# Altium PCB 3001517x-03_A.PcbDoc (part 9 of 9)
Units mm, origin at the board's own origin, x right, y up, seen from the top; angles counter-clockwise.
Board outline 100 x 72 mm, 10 copper layers (Top, GND_2, Signal_3, Signal_4, PWR_5, GND_6, Signal_7, Signal_8, GND_9, Bottom), stack 1.6 mm thick; 602 components, 497 nets, 2372 pads, 1602 vias.

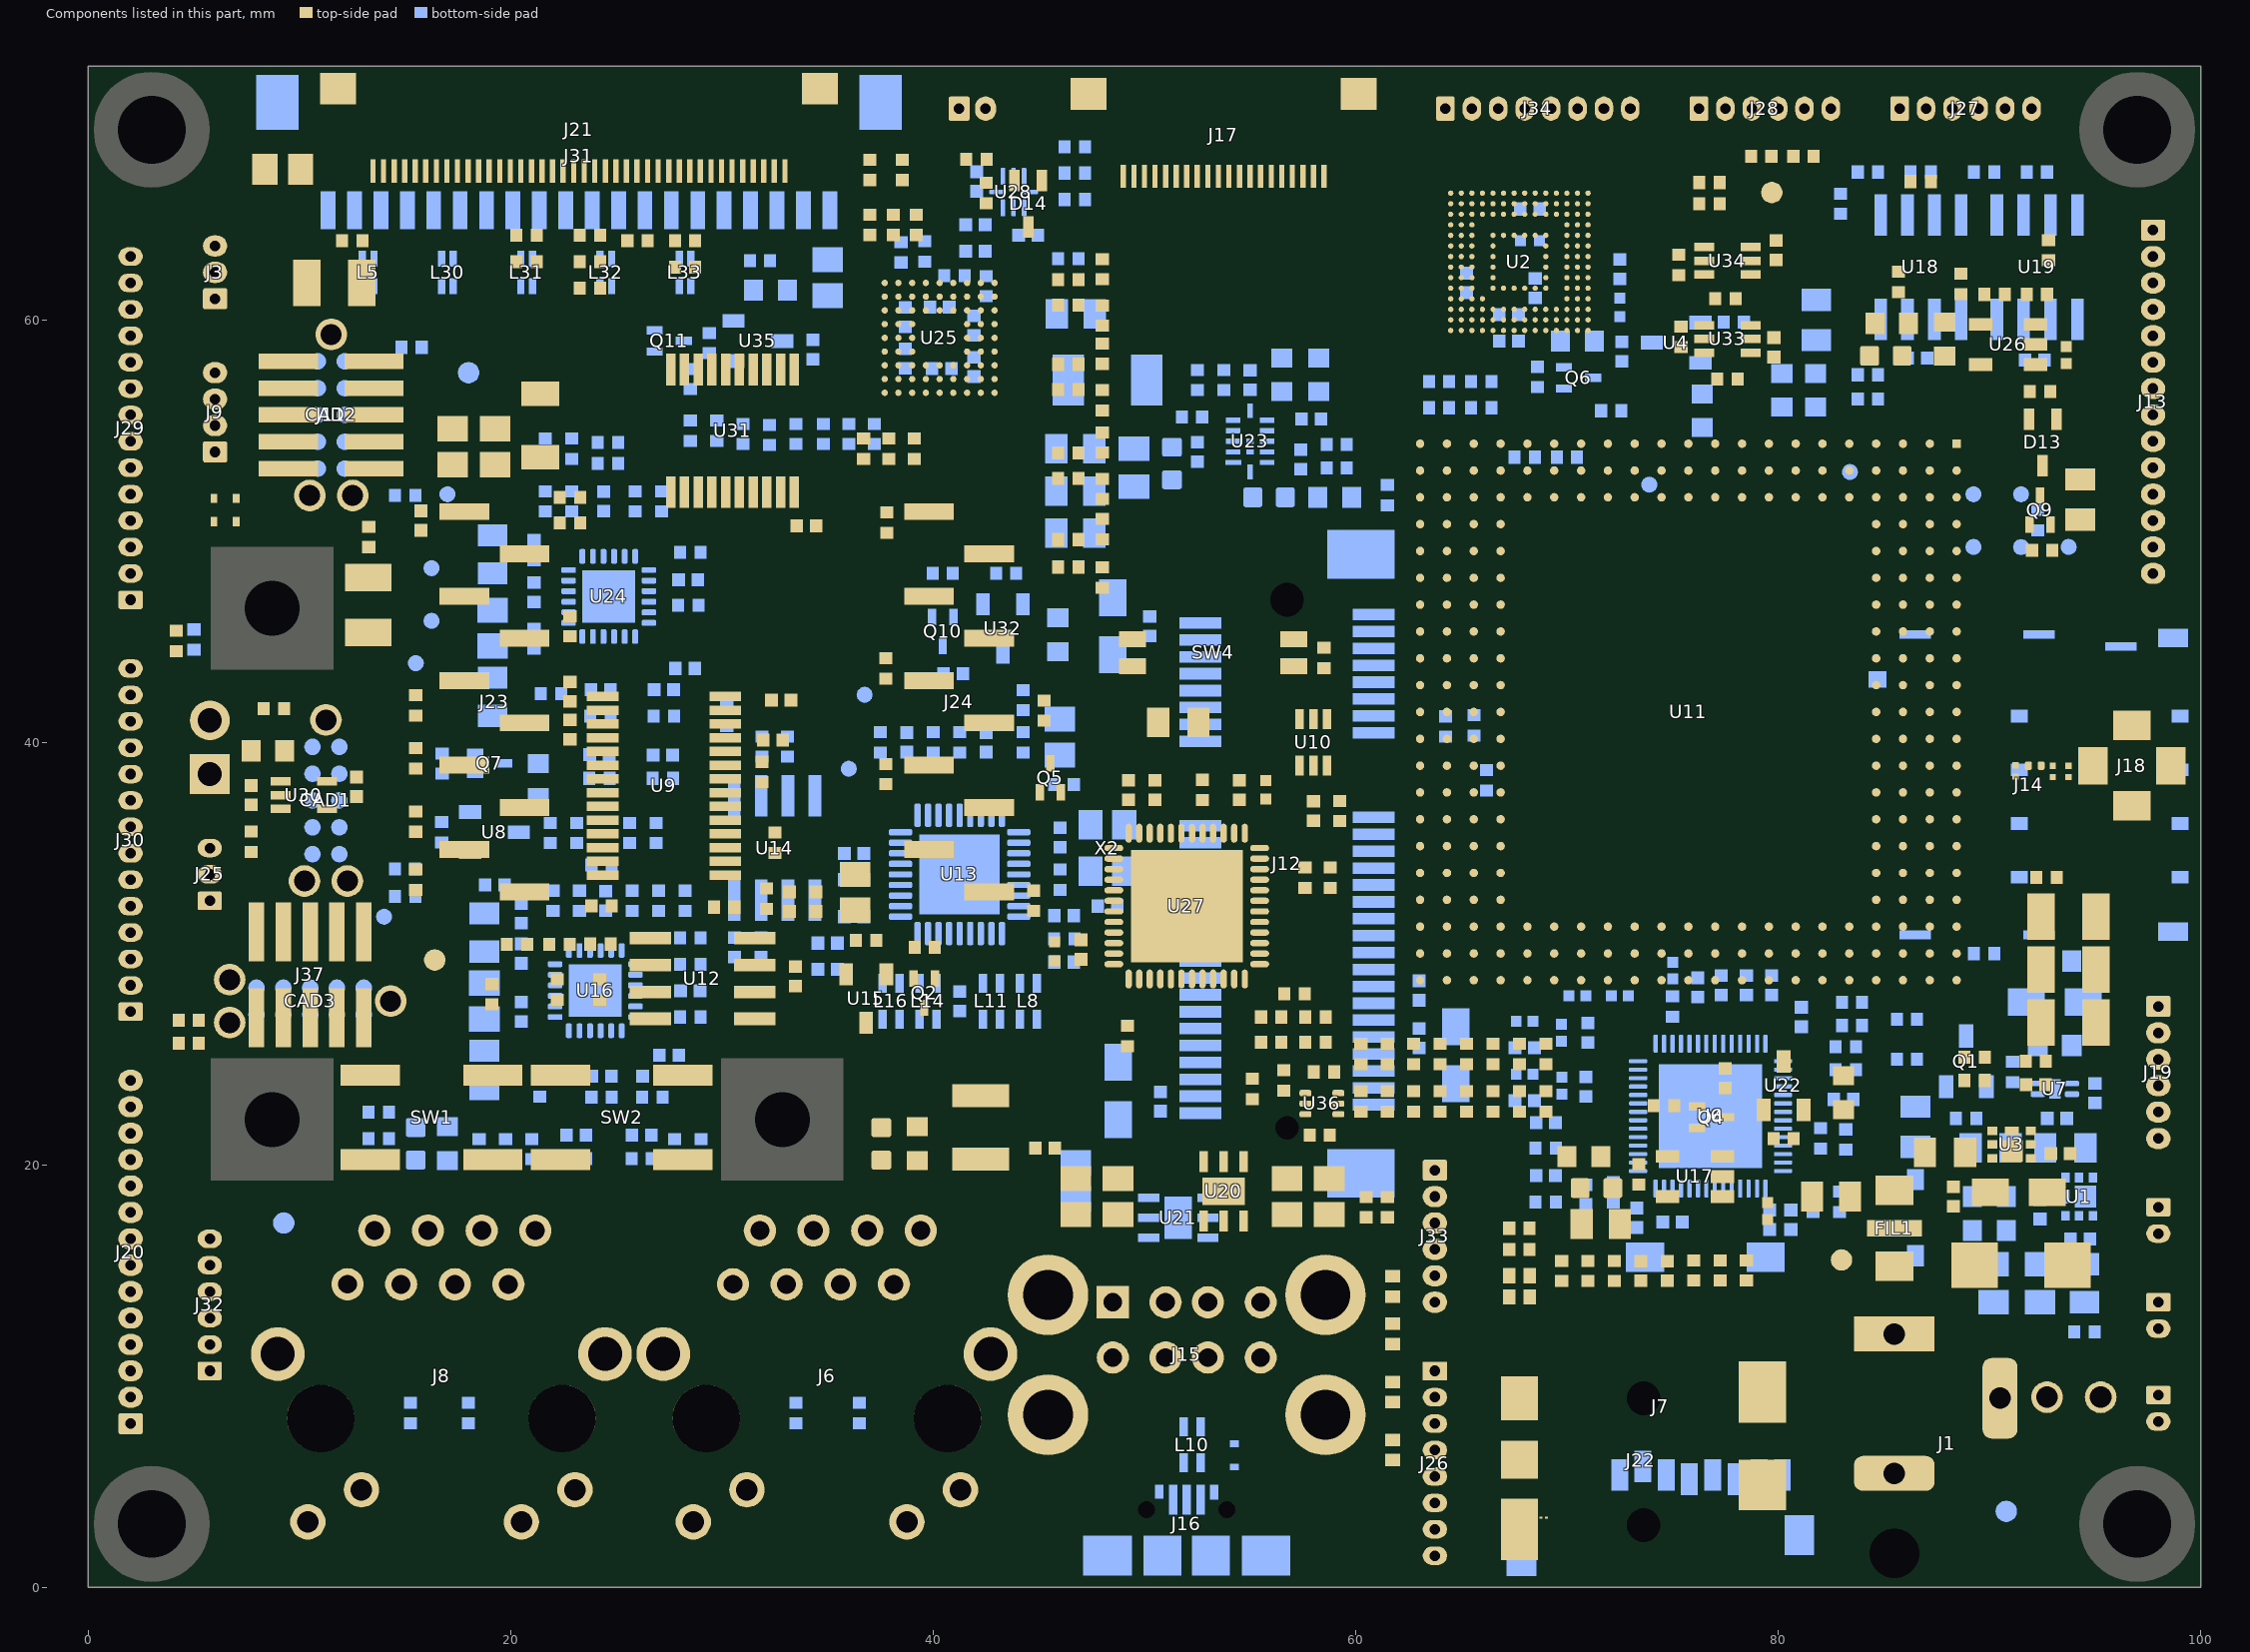
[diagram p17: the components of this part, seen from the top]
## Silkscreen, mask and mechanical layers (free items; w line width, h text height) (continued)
Panel:
  lines w0.1: 68.471,50.54 83.093,50.54 cw(c83.093,50.053) 83.58,50.053 83.58,32.863 cw(c83.057,32.863) 83.057,32.34 68.5,32.34 cw(c68.5,32.92) 67.92,32.92 67.92,49.96 cw(c68.5,49.96) 68.5,50.54 ; 170.971,50.54 185.593,50.54 cw(c185.593,50.053) 186.08,50.053 186.08,32.863 cw(c185.557,32.863) 185.557,32.34 171,32.34 cw(c171,32.92) 170.42,32.92 170.42,49.96 cw(c171,49.96) 171,50.54 ; 273.471,50.54 288.093,50.54 cw(c288.093,50.053) 288.58,50.053 288.58,32.863 cw(c288.057,32.863) 288.057,32.34 273.5,32.34 cw(c273.5,32.92) 272.92,32.92 272.92,49.96 cw(c273.5,49.96) 273.5,50.54
  lines w0.25: 192.5,74.5 215,74.5 cw(c215,73.25) 215,72 205,72 205,62 cw(c203.75,62) 202.5,62 202.5,72 192.54,72 cw(c192.54,73.25) 192.54,74.5 ; 287.5,72 222.5,72 cw(c222.5,73.25) 222.5,74.5 287.5,74.5 ; 287.58,72 ccw(c287.58,73.25) 287.58,74.5 ; 295,72 305,72 305,62 ccw(c306.25,62) 307.5,62 307.5,72 ccw(c305,72) 305,74.5 295,74.5 ; 295.08,72 cw(c295.08,73.25) 295.08,74.5 ; 60.975,0 cw(c60.975,-1.25) 62.225,-1.25 ; 60.975,0 cw(c60.975,-1.25) 62.225,-1.25 ; 60.975,0 0,0 0,10 ccw(c-1.25,10) -2.5,10 -2.5,-2.75 ccw(c-1.25,-2.75) -1.25,-4 60.975,-4 ccw(c60.975,-2.75) 62.225,-2.75 62.225,-1.25 ; 66.225,-1.25 cw(c67.475,-1.25) 67.475,0 ; 66.225,-1.25 cw(c67.475,-1.25) 67.475,0 ; 66.225,-1.25 66.225,-2.75 ccw(c67.475,-2.75) 67.475,-4 93,-4 163.475,-4 ccw(c163.475,-2.75) 164.725,-2.75 164.725,-1.25 ccw(c163.475,-1.25) 163.475,0 102.5,0 102.5,10 ccw(c101.25,10) 100,10 100,0 67.475,0 ; -15,-11.5 -15,79.5 320,79.5 320,-11.5 -15,-11.5 ; -2.5,17.5 ccw(c-1.25,17.5) 0,17.5 0,54.5 ccw(c-1.25,54.5) -2.5,54.5 -2.5,17.5 ; -2.5,62 ccw(c-1.25,62) 0,62 0,72 10,72 ccw(c10,73.25) 10,74.5 0,74.5 ccw(c0,72) -2.5,72 -2.5,62 ; 17.5,72 cw(c17.5,73.25) 17.5,74.5 82.5,74.5 cw(c82.5,73.25) 82.5,72 17.5,72 ; 90,72 cw(c90,73.25) 90,74.5 112.54,74.5 cw(c112.54,73.25) 112.54,72 102.5,72 102.5,62 cw(c101.25,62) 100,62 100,72 90,72 ; 100,16.25 ccw(c101.25,16.25) 102.5,16.25 102.5,54.5 ccw(c101.25,54.5) 100,54.5 100,16.25 ; 120,72 cw(c120,73.25) 120,74.5 185,74.5 cw(c185,73.25) 185,72 120,72 ; 168.725,-2.75 ccw(c169.975,-2.75) 169.975,-4 266.05,-4 ccw(c266.05,-2.75) 267.3,-2.75 267.3,-1.25 ccw(c266.05,-1.25) 266.05,0 205,0 205,10 ccw(c203.75,10) 202.5,10 202.5,0 169.975,0 ccw(c169.975,-1.25) 168.725,-1.25 168.725,-2.75 ; 202.5,16.25 ccw(c203.75,16.25) 205,16.25 205,54.5 ccw(c203.75,54.5) 202.5,54.5 202.5,16.25 ; 271.3,-2.75 ccw(c272.55,-2.75) 272.55,-4 306.25,-4 ccw(c306.25,-2.75) 307.5,-2.75 307.5,10 ccw(c306.25,10) 305,10 305,0 272.55,0 ccw(c272.55,-1.25) 271.3,-1.25 271.3,-2.75 ; 305,16.25 ccw(c306.25,16.25) 307.5,16.25 307.5,54.5 ccw(c306.25,54.5) 305,54.5 305,16.25
  text ".Layer_Name" at 41.25,-18.875 h2.54
PCB Name:
  text "CC6UL SBC" at 36.25,-24.125 h2.54
Fab/Dimension:
  circle w0.05: c3,3 r3.111
  circle w0.05: c3,69 r3.111
  circle w0.05: c97,69 r3.111
  circle w0.05: c97,3 r3.111
Sheet Graphics:
  drawing of 726 lines, arcs and shapes, not listed
  text "1" at 333.273,124.993 h4.57
  text "4" at -85.192,124.358 h4.57
  text "3" at 57.048,124.358 h4.57
  text "2" at 196.113,123.723 h4.57
  text "D" at -145.517,85.623 h7.11
  text "D" at 399.821,81.178 h7.11
  text "CUT OUT" at 45.695,72.644 h1.25
  text "CUT OUT" at 1.27,72.593 h1.25
  text "CUT OUT" at 153.492,72.593 h1.25
  text "CUT OUT" at 254.356,72.593 h1.25
  text "CUT OUT" at 101.981,63.754 h1.25 r90
  text "CUT OUT" at 204.394,63.703 h1.25 r90
  text "CUT OUT" at 306.908,63.043 h1.25 r90
  text "CUT OUT" at 71,39.5 h1.5
  text "CUT OUT" at 204.445,31.521 h1.25 r90
  text "CUT OUT" at -0.66,30.734 h1.25 r90
  text "CUT OUT" at 306.934,28.245 h1.25 r90
  text "CUT OUT" at 101.981,27.584 h1.25 r90
  text "CUT OUT" at 25.248,-2.616 h1.5
  text "CUT OUT" at 107.823,-2.718 h1.5
  text "CUT OUT" at 213.639,-2.896 h1.5
  text "CUT OUT" at 286.233,-2.896 h1.5
  text "C" at -145.517,-23.597 h7.11
  text "C" at 398.551,-23.597 h7.11
  text "1. Manufacture in accordance with IPC-6012, class 2. Inspect to IPC-A-600, class 2." at 185,-30 h6
  text "T" at -120.344,-41.271 h4.76
  text "a" at -118.436,-41.271 h4.76
  text "r" at -116.529,-41.271 h4.76
  text "g" at -115.166,-41.271 h4.76
  text "e" at -113.259,-41.271 h4.76
  text "t" at -111.078,-41.271 h4.76
  text "T" at -103.335,-41.271 h4.76
  text "o" at -101.427,-41.271 h4.76
  text "l" at -99.247,-41.271 h4.76
  text "+" at -97.34,-41.271 h4.76
  text "/" at -95.432,-41.271 h4.76
  text "-" at -93.797,-41.271 h4.76
  text "%" at -92.435,-41.271 h4.76
  text "L" at -87.577,-41.271 h4.76
  text "a" at -85.942,-41.271 h4.76
  text "y" at -84.034,-41.271 h4.76
  text "e" at -82.127,-41.271 h4.76
  text "r" at -79.947,-41.271 h4.76
  text "N" at -77.767,-41.271 h4.76
  text "o" at -75.042,-41.271 h4.76
  text "." at -72.862,-41.271 h4.76
  text "T" at -69.818,-41.271 h4.76
  text "r" at -67.91,-41.271 h4.76
  text "a" at -66.548,-41.271 h4.76
  text "c" at -64.64,-41.271 h4.76
  text "e" at -63.005,-41.271 h4.76
  text "C" at -60.007,-41.271 h4.76
  text "l" at -57.827,-41.271 h4.76
  text "e" at -56.737,-41.271 h4.76
  text "a" at -54.557,-41.271 h4.76
  text "r" at -52.65,-41.271 h4.76
  text "a" at -51.287,-41.271 h4.76
  text "n" at -49.38,-41.271 h4.76
  text "c" at -47.2,-41.271 h4.76
  text "e" at -45.565,-41.271 h4.76
  text "T" at -40.052,-41.271 h4.76
  text "r" at -38.145,-41.271 h4.76
  text "a" at -36.782,-41.271 h4.76
  text "c" at -34.875,-41.271 h4.76
  text "e" at -33.24,-41.271 h4.76
  text "W" at -30.242,-41.271 h4.76
  text "i" at -26.427,-41.271 h4.76
  text "d" at -25.337,-41.271 h4.76
  text "t" at -23.157,-41.271 h4.76
  text "h" at -21.795,-41.271 h4.76
  text "C" at -10.787,-41.271 h4.76
  text "h" at -8.607,-41.271 h4.76
  text "a" at -6.427,-41.271 h4.76
  text "r" at -4.52,-41.271 h4.76
  text "a" at -3.157,-41.271 h4.76
  text "c" at -1.25,-41.271 h4.76
  text "t" at 0.385,-41.271 h4.76
  text "e" at 1.748,-41.271 h4.76
  text "r" at 3.928,-41.271 h4.76
  text "i" at 5.291,-41.271 h4.76
  text "s" at 6.381,-41.271 h4.76
  text "t" at 8.016,-41.271 h4.76
  text "i" at 9.378,-41.271 h4.76
  text "c" at 10.468,-41.271 h4.76
  text "E" at 18.978,-41.271 h4.76
  text "d" at 20.886,-41.271 h4.76
  text "g" at 23.066,-41.271 h4.76
  text "e" at 24.973,-41.271 h4.76
  text "C" at 27.971,-41.271 h4.76
  text "o" at 30.151,-41.271 h4.76
  text "u" at 32.331,-41.271 h4.76
  text "p" at 34.511,-41.271 h4.76
  text "l" at 36.691,-41.271 h4.76
  text "e" at 37.781,-41.271 h4.76
  text "d" at 39.961,-41.271 h4.76
  text "2. Manufacturing process and materials used must comply with ROHS directive / 2002/95/EC." at 185,-45 h6
  text "I" at -124.096,-46.721 h4.76
  text "m" at -123.006,-46.721 h4.76
  text "p" at -119.735,-46.721 h4.76
  text "e" at -117.555,-46.721 h4.76
  text "d" at -115.375,-46.721 h4.76
  text "a" at -113.195,-46.721 h4.76
  text "n" at -111.288,-46.721 h4.76
  text "c" at -109.108,-46.721 h4.76
  text "e" at -107.473,-46.721 h4.76
  text "(" at -61.813,-46.721 h4.76
  text "M" at -60.451,-46.721 h4.76
  text "I" at -56.908,-46.721 h4.76
  text "L" at -55.818,-46.721 h4.76
  text ")" at -54.183,-46.721 h4.76
  text "(" at -34.8,-46.721 h4.76
  text "M" at -33.437,-46.721 h4.76
  text "I" at -29.895,-46.721 h4.76
  text "L" at -28.805,-46.721 h4.76
  text ")" at -27.169,-46.721 h4.76
  text "I" at -12.538,-46.721 h4.76
  text "m" at -11.448,-46.721 h4.76
  text "p" at -8.178,-46.721 h4.76
  text "e" at -5.998,-46.721 h4.76
  text "d" at -3.818,-46.721 h4.76
  text "a" at -1.638,-46.721 h4.76
  text "n" at 0.27,-46.721 h4.76
  text "c" at 2.45,-46.721 h4.76
  text "e" at 4.085,-46.721 h4.76
  text "(" at 7.082,-46.721 h4.76
  text "Z" at 8.445,-46.721 h4.76
  text "o" at 10.352,-46.721 h4.76
  text ")" at 12.532,-46.721 h4.76
  text "D" at 20.729,-46.721 h4.76
  text "i" at 23.182,-46.721 h4.76
  text "f" at 24.272,-46.721 h4.76
  text "f" at 25.634,-46.721 h4.76
  text "e" at 26.997,-46.721 h4.76
  text "r" at 29.177,-46.721 h4.76
  text "e" at 30.539,-46.721 h4.76
  text "n" at 32.719,-46.721 h4.76
  text "t" at 34.899,-46.721 h4.76
  text "i" at 36.262,-46.721 h4.76
  text "a" at 37.352,-46.721 h4.76
  text "l" at 39.259,-46.721 h4.76
  text "(" at 24.731,-52.171 h4.76
  text "Z" at 26.094,-52.171 h4.76
  text "d" at 28.001,-52.171 h4.76
  text "i" at 30.181,-52.171 h4.76
  text "f" at 31.271,-52.171 h4.76
  text "f" at 32.634,-52.171 h4.76
  text ")" at 33.996,-52.171 h4.76
  text "D" at -125.846,-57.894 h4.76
  text "I" at -123.394,-57.894 h4.76
  text "F" at -122.304,-57.894 h4.76
  text "F" at -120.396,-57.894 h4.76
  text "_" at -118.489,-57.894 h4.76
  text "1" at -116.581,-57.894 h4.76
  text "0" at -114.674,-57.894 h4.76
  text "0" at -112.766,-57.894 h4.76
  text "o" at -110.859,-57.894 h4.76
  text "h" at -108.679,-57.894 h4.76
  text "m" at -106.499,-57.894 h4.76
  text "1" at -98.582,-57.894 h4.76
  text "0" at -96.675,-57.894 h4.76
  text "3" at -81.073,-57.894 h4.76
  text "8" at -58.312,-57.894 h4.76
  text "5" at -31.548,-57.894 h4.76
  text "5" at -4.284,-57.894 h4.76
  text "5" at -2.376,-57.894 h4.76
  text "." at -0.469,-57.894 h4.76
  text "3" at 0.621,-57.894 h4.76
  text "6" at 2.529,-57.894 h4.76
  text "1" at 24.981,-57.894 h4.76
  text "0" at 26.889,-57.894 h4.76
  text "0" at 28.796,-57.894 h4.76
  text "." at 30.704,-57.894 h4.76
  text "3" at 31.794,-57.894 h4.76
  text "8" at 33.701,-57.894 h4.76
  text "D" at -125.846,-63.344 h4.76
  text "I" at -123.394,-63.344 h4.76
  text "F" at -122.304,-63.344 h4.76
  text "F" at -120.396,-63.344 h4.76
  text "_" at -118.489,-63.344 h4.76
  text "1" at -116.581,-63.344 h4.76
  text "0" at -114.674,-63.344 h4.76
  text "0" at -112.766,-63.344 h4.76
  text "o" at -110.859,-63.344 h4.76
  text "h" at -108.679,-63.344 h4.76
  text "m" at -106.499,-63.344 h4.76
  text "1" at -98.582,-63.344 h4.76
  text "0" at -96.675,-63.344 h4.76
  text "8" at -81.073,-63.344 h4.76
  text "8" at -58.312,-63.344 h4.76
  text "5" at -31.548,-63.344 h4.76
  text "5" at -4.284,-63.344 h4.76
  text "5" at -2.376,-63.344 h4.76
  text "." at -0.469,-63.344 h4.76
  text "3" at 0.621,-63.344 h4.76
  text "6" at 2.529,-63.344 h4.76
  text "1" at 24.981,-63.344 h4.76
  text "0" at 26.889,-63.344 h4.76
  text "0" at 28.796,-63.344 h4.76
  text "." at 30.704,-63.344 h4.76
  text "3" at 31.794,-63.344 h4.76
  text "8" at 33.701,-63.344 h4.76
  text "3. MATERIAL: ITEQ IT-180A /     Material should comply with IPC-4104/99/101/126 /     See Stack-up for details." at 185,-65 h6
  text "D" at -124.846,-68.794 h4.76
  text "I" at -122.393,-68.794 h4.76
  text "F" at -121.303,-68.794 h4.76
  text "F" at -119.396,-68.794 h4.76
  text "_" at -117.488,-68.794 h4.76
  text "9" at -115.581,-68.794 h4.76
  text "0" at -113.673,-68.794 h4.76
  text "o" at -111.766,-68.794 h4.76
  text "h" at -109.586,-68.794 h4.76
  text "m" at -107.406,-68.794 h4.76
  text "1" at -98.582,-68.794 h4.76
  text "0" at -96.675,-68.794 h4.76
  text "3" at -81.073,-68.794 h4.76
  text "8" at -58.312,-68.794 h4.76
  text "6" at -32.799,-68.794 h4.76
  text "." at -30.891,-68.794 h4.76
  text "5" at -29.801,-68.794 h4.76
  text "4" at -4.284,-68.794 h4.76
  text "8" at -2.376,-68.794 h4.76
  text "." at -0.469,-68.794 h4.76
  text "8" at 0.621,-68.794 h4.76
  text "8" at 2.529,-68.794 h4.76
  text "8" at 25.732,-68.794 h4.76
  text "9" at 27.639,-68.794 h4.76
  text "." at 29.547,-68.794 h4.76
  text "7" at 30.637,-68.794 h4.76
  text "6" at 32.544,-68.794 h4.76
  text "4. SURFACE FINISH: Apply ENIG to all exposed copper per IPC-4552." at 185,-72.5 h6
  text "D" at -124.846,-74.244 h4.76
  text "I" at -122.393,-74.244 h4.76
  text "F" at -121.303,-74.244 h4.76
  text "F" at -119.396,-74.244 h4.76
  text "_" at -117.488,-74.244 h4.76
  text "9" at -115.581,-74.244 h4.76
  text "0" at -113.673,-74.244 h4.76
  text "o" at -111.766,-74.244 h4.76
  text "h" at -109.586,-74.244 h4.76
  text "m" at -107.406,-74.244 h4.76
  text "1" at -98.582,-74.244 h4.76
  text "0" at -96.675,-74.244 h4.76
  text "7" at -81.073,-74.244 h4.76
  text "8" at -58.312,-74.244 h4.76
  text "6" at -32.799,-74.244 h4.76
  text "." at -30.891,-74.244 h4.76
  text "5" at -29.801,-74.244 h4.76
  text "4" at -4.284,-74.244 h4.76
  text "8" at -2.376,-74.244 h4.76
  text "." at -0.469,-74.244 h4.76
  text "8" at 0.621,-74.244 h4.76
  text "8" at 2.529,-74.244 h4.76
  text "8" at 25.732,-74.244 h4.76
  text "9" at 27.639,-74.244 h4.76
  text "." at 29.547,-74.244 h4.76
  text "7" at 30.637,-74.244 h4.76
  text "6" at 32.544,-74.244 h4.76
  text "D" at -124.846,-79.694 h4.76
  text "I" at -122.393,-79.694 h4.76
  text "F" at -121.303,-79.694 h4.76
  text "F" at -119.396,-79.694 h4.76
  text "_" at -117.488,-79.694 h4.76
  text "9" at -115.581,-79.694 h4.76
  text "0" at -113.673,-79.694 h4.76
  text "o" at -111.766,-79.694 h4.76
  text "h" at -109.586,-79.694 h4.76
  text "m" at -107.406,-79.694 h4.76
  text "1" at -98.582,-79.694 h4.76
  text "0" at -96.675,-79.694 h4.76
  text "8" at -81.073,-79.694 h4.76
  text "8" at -58.312,-79.694 h4.76
  text "6" at -32.799,-79.694 h4.76
  text "." at -30.891,-79.694 h4.76
  text "5" at -29.801,-79.694 h4.76
  text "4" at -4.284,-79.694 h4.76
  text "8" at -2.376,-79.694 h4.76
  text "." at -0.469,-79.694 h4.76
  text "8" at 0.621,-79.694 h4.76
  text "8" at 2.529,-79.694 h4.76
  text "8" at 25.732,-79.694 h4.76
  text "9" at 27.639,-79.694 h4.76
  text "." at 29.547,-79.694 h4.76
  text "7" at 30.637,-79.694 h4.76
  text "6" at 32.544,-79.694 h4.76
  text "5. Starting copper weight is 1/2oz. on all layers" at 185,-80 h6
  text "D" at -124.846,-85.144 h4.76
  text "I" at -122.393,-85.144 h4.76
  text "F" at -121.303,-85.144 h4.76
  text "F" at -119.396,-85.144 h4.76
  text "_" at -117.488,-85.144 h4.76
  text "9" at -115.581,-85.144 h4.76
  text "0" at -113.673,-85.144 h4.76
  text "o" at -111.766,-85.144 h4.76
  text "h" at -109.586,-85.144 h4.76
  text "m" at -107.406,-85.144 h4.76
  text "1" at -98.582,-85.144 h4.76
  text "0" at -96.675,-85.144 h4.76
  text "1" at -81.824,-85.144 h4.76
  text "0" at -79.916,-85.144 h4.76
  text "8" at -58.312,-85.144 h4.76
  text "5" at -31.548,-85.144 h4.76
  text "4" at -4.284,-85.144 h4.76
  text "8" at -2.376,-85.144 h4.76
  text "." at -0.469,-85.144 h4.76
  text "9" at 0.621,-85.144 h4.76
  text "5" at 2.529,-85.144 h4.76
  text "9" at 25.732,-85.144 h4.76
  text "0" at 27.639,-85.144 h4.76
  text "." at 29.547,-85.144 h4.76
  text "5" at 30.637,-85.144 h4.76
  text "2" at 32.544,-85.144 h4.76
  text "5" at -125.846,-90.594 h4.76
  text "0" at -123.939,-90.594 h4.76
  text "o" at -122.031,-90.594 h4.76
  text "h" at -119.851,-90.594 h4.76
  text "m" at -117.671,-90.594 h4.76
  text "_" at -114.401,-90.594 h4.76
  text "C" at -112.494,-90.594 h4.76
  text "H" at -110.314,-90.594 h4.76
  text "A" at -107.861,-90.594 h4.76
  text "R" at -105.409,-90.594 h4.76
  text "1" at -98.582,-90.594 h4.76
  text "0" at -96.675,-90.594 h4.76
  text "1" at -81.073,-90.594 h4.76
  text "N" at -60.563,-90.594 h4.76
  text "/" at -57.838,-90.594 h4.76
  text "A" at -56.203,-90.594 h4.76
  text "4" at -32.799,-90.594 h4.76
  text "." at -30.891,-90.594 h4.76
  text "7" at -29.801,-90.594 h4.76
  text "5" at -4.284,-90.594 h4.76
  text "0" at -2.376,-90.594 h4.76
  text "." at -0.469,-90.594 h4.76
  text "4" at 0.621,-90.594 h4.76
  text "3" at 2.529,-90.594 h4.76
  text "N" at 26.732,-90.594 h4.76
  text "/" at 29.457,-90.594 h4.76
  text "A" at 31.092,-90.594 h4.76
  text "6. SOLDER MASK: LPI over bare copper. / SOLDER MASK COLOR: BLUE" at 185,-95 h6
  text "5" at -125.846,-96.044 h4.76
  text "0" at -123.939,-96.044 h4.76
  text "o" at -122.031,-96.044 h4.76
  text "h" at -119.851,-96.044 h4.76
  text "m" at -117.671,-96.044 h4.76
  text "_" at -114.401,-96.044 h4.76
  text "C" at -112.494,-96.044 h4.76
  text "H" at -110.314,-96.044 h4.76
  text "A" at -107.861,-96.044 h4.76
  text "R" at -105.409,-96.044 h4.76
  text "1" at -98.582,-96.044 h4.76
  text "0" at -96.675,-96.044 h4.76
  text "3" at -81.073,-96.044 h4.76
  text "N" at -60.563,-96.044 h4.76
  text "/" at -57.838,-96.044 h4.76
  text "A" at -56.203,-96.044 h4.76
  text "5" at -31.548,-96.044 h4.76
  text "4" at -4.284,-96.044 h4.76
  text "8" at -2.376,-96.044 h4.76
  text "." at -0.469,-96.044 h4.76
  text "3" at 0.621,-96.044 h4.76
  text "8" at 2.529,-96.044 h4.76
  text "N" at 26.732,-96.044 h4.76
  text "/" at 29.457,-96.044 h4.76
  text "A" at 31.092,-96.044 h4.76
  text "5" at -125.846,-101.494 h4.76
  text "0" at -123.939,-101.494 h4.76
  text "o" at -122.031,-101.494 h4.76
  text "h" at -119.851,-101.494 h4.76
  text "m" at -117.671,-101.494 h4.76
  text "_" at -114.401,-101.494 h4.76
  text "C" at -112.494,-101.494 h4.76
  text "H" at -110.314,-101.494 h4.76
  text "A" at -107.861,-101.494 h4.76
  text "R" at -105.409,-101.494 h4.76
  text "1" at -98.582,-101.494 h4.76
  text "0" at -96.675,-101.494 h4.76
  text "7" at -81.073,-101.494 h4.76
  text "N" at -60.563,-101.494 h4.76
  text "/" at -57.838,-101.494 h4.76
  text "A" at -56.203,-101.494 h4.76
  text "5" at -31.548,-101.494 h4.76
  text "5" at -4.284,-101.494 h4.76
  text "0" at -2.376,-101.494 h4.76
  text "." at -0.469,-101.494 h4.76
  text "3" at 0.621,-101.494 h4.76
  text "5" at 2.529,-101.494 h4.76
  text "N" at 26.732,-101.494 h4.76
  text "/" at 29.457,-101.494 h4.76
  text "A" at 31.092,-101.494 h4.76
  text "5" at -125.846,-106.944 h4.76
  text "0" at -123.939,-106.944 h4.76
  text "o" at -122.031,-106.944 h4.76
  text "h" at -119.851,-106.944 h4.76
  text "m" at -117.671,-106.944 h4.76
  text "_" at -114.401,-106.944 h4.76
  text "C" at -112.494,-106.944 h4.76
  text "H" at -110.314,-106.944 h4.76
  text "A" at -107.861,-106.944 h4.76
  text "R" at -105.409,-106.944 h4.76
  text "1" at -98.582,-106.944 h4.76
  text "0" at -96.675,-106.944 h4.76
  text "8" at -81.073,-106.944 h4.76
  text "N" at -60.563,-106.944 h4.76
  text "/" at -57.838,-106.944 h4.76
  text "A" at -56.203,-106.944 h4.76
  text "5" at -31.548,-106.944 h4.76
  text "5" at -4.284,-106.944 h4.76
  text "0" at -2.376,-106.944 h4.76
  text "." at -0.469,-106.944 h4.76
  text "3" at 0.621,-106.944 h4.76
  text "5" at 2.529,-106.944 h4.76
  text "N" at 26.732,-106.944 h4.76
  text "/" at 29.457,-106.944 h4.76
  text "A" at 31.092,-106.944 h4.76
  text "5" at -125.846,-112.394 h4.76
  text "0" at -123.939,-112.394 h4.76
  text "o" at -122.031,-112.394 h4.76
  text "h" at -119.851,-112.394 h4.76
  text "m" at -117.671,-112.394 h4.76
  text "_" at -114.401,-112.394 h4.76
  text "C" at -112.494,-112.394 h4.76
  text "H" at -110.314,-112.394 h4.76
  text "A" at -107.861,-112.394 h4.76
  text "R" at -105.409,-112.394 h4.76
  text "1" at -98.582,-112.394 h4.76
  text "0" at -96.675,-112.394 h4.76
  text "1" at -81.824,-112.394 h4.76
  text "0" at -79.916,-112.394 h4.76
  text "N" at -60.563,-112.394 h4.76
  text "/" at -57.838,-112.394 h4.76
  text "A" at -56.203,-112.394 h4.76
  text "4" at -32.799,-112.394 h4.76
  text "." at -30.891,-112.394 h4.76
  text "7" at -29.801,-112.394 h4.76
  text "5" at -4.284,-112.394 h4.76
  text "0" at -2.376,-112.394 h4.76
  text "." at -0.469,-112.394 h4.76
  text "4" at 0.621,-112.394 h4.76
  text "3" at 2.529,-112.394 h4.76
  text "N" at 26.732,-112.394 h4.76
  text "/" at 29.457,-112.394 h4.76
  text "A" at 31.092,-112.394 h4.76
  text "7. SILKSCREEN: Apply on top and bottom sides of PCB. / High accuracy required for QR code on Bottom Overlay. / SILKSCREEN COLOR: WHITE" at 185,-117.5 h6
  text "Layer" at -125.494,-122 h2
  text "Name" at -111.989,-122 h2
  text "Material" at -81.156,-122 h2
  text "Thickness" at -18,-122 h2
  text "Constant" at 3.503,-122 h2
  text "Board Layer Stack" at 22.339,-122 h2
  text "1" at -125.494,-126 h2
  text "Top Overlay" at -111.989,-126 h2
  text "B" at -145.517,-129.642 h7.11
  text "B" at 398.551,-129.642 h7.11
  text "2" at -125.494,-130 h2
  text "Top Solder" at -111.989,-130 h2
  text "Dielectric" at -81.156,-130 h2
  text "0.50mil" at -18,-130 h2
  text "3.3" at 3.503,-130 h2
  text "8. GERBER FILE FORMAT: 274-X WITH 4/3 accuracy (XXXX.XXX). / Gerber and drill in mm." at 185,-132.5 h6
  text "3" at -125.494,-134 h2
  text "Top" at -111.989,-134 h2
  text "Copper" at -81.156,-134 h2
  text "1.70mil" at -18,-134 h2
  text "4" at -125.494,-138 h2
  text "Dielectric1" at -111.989,-138 h2
  text "IT-180A; 1086; Rc62%; (2GHz)" at -81.156,-138 h2
  text "2.99mil" at -18,-138 h2
  text "3.9" at 3.503,-138 h2
  text "5" at -125.494,-142 h2
  text "GND_2" at -111.989,-142 h2
  text "Copper" at -81.156,-142 h2
  text "0.70mil" at -18,-142 h2
  text "9. Maximum warp and twist per IPC-6012 of 0.75% inch/inch." at 185,-142.5 h6
  text "6" at -125.494,-146 h2
  text "Dielectric2" at -111.989,-146 h2
  text "IT-180A; 2-1080; (2GHz)" at -81.156,-146 h2
  text "5.00mil" at -18,-146 h2
  text "3.7" at 3.503,-146 h2
  text "7" at -125.494,-150 h2
  text "Signal_3" at -111.989,-150 h2
  text "Copper" at -81.156,-150 h2
  text "0.70mil" at -18,-150 h2
  text "8" at -125.494,-154 h2
  text "Dielectric3" at -111.989,-154 h2
  text "IT-180A; 1067; Rc71%; (2GHz) x2" at -81.156,-154 h2
  text "5.00mil" at -18,-154 h2
  text "3.9" at 3.503,-154 h2
  text "9" at -125.494,-158 h2
  text "Signal_4" at -111.989,-158 h2
  text "Copper" at -81.156,-158 h2
  text "0.70mil" at -18,-158 h2
  text "10. Copper thieving is NOT allowed within board outline. / Thieving may be placed in array rails." at 185,-160 h6
  text "10" at -125.494,-162 h2
  text "Dielectric 13" at -111.989,-162 h2
  text "IT-180A; 2-1080; (2GHz)" at -81.156,-162 h2
  text "5.00mil" at -18,-162 h2
  text "3.7" at 3.503,-162 h2
  text "11" at -125.494,-166 h2
  text "PWR_5" at -111.989,-166 h2
  text "Copper" at -81.156,-166 h2
  text "0.70mil" at -18,-166 h2
  text "12" at -125.494,-170 h2
  text "Dielectric6" at -111.989,-170 h2
  text "IT-180A" at -81.156,-170 h2
  text "17.99mil" at -18,-170 h2
  text "3.9" at 3.503,-170 h2
  text "13" at -125.494,-174 h2
  text "GND_6" at -111.989,-174 h2
  text "Copper" at -81.156,-174 h2
  text "0.70mil" at -18,-174 h2
  text "14" at -125.494,-178 h2
  text "Dielectric9" at -111.989,-178 h2
  text "IT-180A; 2-1080; (2GHz)" at -81.156,-178 h2
  text "5.00mil" at -18,-178 h2
  text "3.7" at 3.503,-178 h2
  text "15" at -125.494,-182 h2
  text "Signal_7" at -111.989,-182 h2
  text "Copper" at -81.156,-182 h2
  text "0.70mil" at -18,-182 h2
  text "11. Plated holes are specified as finished hole sizes (see table). / Plated hole tolerance ±0.003\" (±76µm) / NPTH tolerance ±0.0015\" (±38.1µm)" at 185,-182.5 h6
  text "16" at -125.494,-186 h2
  text "Dielectric10" at -111.989,-186 h2
  text "IT-180A; 1067; Rc71%; (2GHz) x2" at -81.156,-186 h2
  text "5.00mil" at -18,-186 h2
  text "3.9" at 3.503,-186 h2
  text "17" at -125.494,-190 h2
  text "Signal_8" at -111.989,-190 h2
  text "Copper" at -81.156,-190 h2
  text "0.70mil" at -18,-190 h2
  text "12. Slot/Cut-Out tolerance ±0.005\" (±127µm)" at 185,-190 h6
  text "18" at -125.494,-194 h2
  text "Dielectric 12" at -111.989,-194 h2
  text "IT-180A; 2-1080; (2GHz)" at -81.156,-194 h2
  text "5.00mil" at -18,-194 h2
  text "3.7" at 3.503,-194 h2
  text "19" at -125.494,-198 h2
  text "GND_9" at -111.989,-198 h2
  text "Copper" at -81.156,-198 h2
  text "0.70mil" at -18,-198 h2
  text "13. See table for controlled impedance trace widths." at 185,-200 h6
  text "20" at -125.494,-202 h2
  text "Dielectric11" at -111.989,-202 h2
  text "IT-180A; 1086; Rc62%; (2GHz)" at -81.156,-202 h2
  text "2.99mil" at -18,-202 h2
  text "3.9" at 3.503,-202 h2
  text "21" at -125.494,-206 h2
  text "Bottom" at -111.989,-206 h2
  text "Copper" at -81.156,-206 h2
  text "1.70mil" at -18,-206 h2
  text "14. Finished thickness is 0.062\" ±0.006\" (1.57 ± 157µm)" at 185,-207.5 h6
  text "22" at -125.494,-210 h2
  text "Bottom Solder" at -111.989,-210 h2
  text "Dielectric" at -81.156,-210 h2
  text "0.50mil" at -18,-210 h2
  text "3.3" at 3.503,-210 h2
  text "23" at -125.494,-214 h2
  text "Bottom Overlay" at -111.989,-214 h2
  text "15. Intentional short: NetNT1-1 to GND" at 185,-215 h6
  text "A" at -145.085,-222.352 h7.11
  text "A" at 398.983,-222.352 h7.11
  text "CAD GENERATED:" at 337.718,-227.432 h1.27
  text "CAD GENERATED:" at 337.718,-227.432 h1.27
  text ".pcb_File_Name_No_Path" at 353.212,-227.432 h2.17
  text "EXCEPT AS MAY BE OTHERWISE PROVIDED BY" at 238.658,-231.496 h2.17
  text "WIRELESS DESIGN SERVICES" at 332.638,-233.02 h2.54
  text "CONTRACT, THIS DOCUMENT IS THE PROPERTY" at 238.658,-233.528 h2.17
  text "OF DIGI INTERNATIONAL.  IF RELEASED TO OTHER" at 238.658,-235.56 h2.17
  text "11001 Bren Road East" at 332.638,-236.576 h2.54
  text "SOURCES, IT SHALL BE RECEIVED BY SUCH" at 238.658,-237.592 h2.17
  text "SOURCES IN TOTAL CONFIDENCE AND SHALL NOT" at 238.658,-239.624 h2.17
  text "Minnetonka, MN 55343" at 333.146,-240.132 h2.54
  text "BE RELEASED TO ANY THIRD PARTY OR PARTIES," at 238.658,-241.656 h2.17
  text "NOR USED FOR MANUFACTURE OR SALE OF THE" at 238.658,-243.688 h2.17
  text "ARTICLES WITHOUT PRIOR WRITTEN" at 238.658,-245.72 h2.17
  text "DIGI INTERNATIONAL" at 328.574,-246.228 h2.54
  text "AUTHORIZATION." at 238.658,-247.752 h2.17
  text "ConnectCore for i.MX6UL" at 323.596,-250.444 h2.54
  text "ENGINEER" at 238.15,-254.356 h1.27
  text "SINGLE BOARD COMPUTER (SBC)" at 315.976,-254.508 h2.54
  text "SEBASTIEN MEYER" at 255.524,-255.016 h1.27
  text "PCB DESIGNER" at 238.15,-259.436 h1.27
  text "SIZE" at 291.49,-259.436 h1.27
  text "CAGE NO." at 299.618,-259.436 h1.27
  text "PCB NO." at 327.558,-259.436 h1.27
  text "REV." at 389.534,-259.436 h1.27
  text "JOSH FLAGSTAD" at 255.524,-260.096 h1.27
  text "30015172-03" at 343.5,-263.5 h2.54
  text "DATE" at 238.15,-264.008 h1.27
  text "C" at 291.998,-264.008 h2.54
  text "A" at 389.534,-264.008 h2.54
  text ".Print_Date" at 254.914,-265.024 h1.27
  text "JIRA EPIC:" at 238.15,-269.088 h1.27
  text "CC6UL-244" at 254.914,-270.612 h1.27
  text ".Print_Scale" at 289.458,-270.612 h1.27
  text "SVN HEAD REV:" at 314.858,-270.612 h1.27
  text ".VersionControl_RevNumber" at 330.606,-270.612 h1.27
  text "SHEET:" at 352.958,-270.612 h1.27
  text "1 OF 1" at 371.5,-270.612 h1.27
  text "1" at 333.273,-280.137 h4.57
  text "4" at -85.192,-280.772 h4.57
  text "3" at 57.048,-280.772 h4.57
  text "2" at 196.113,-281.407 h4.57
Drill Drawing:
  lines w0.1: 19.5,-104.125 167.638,-104.125 ; 19.5,-29.125 167.638,-29.125 ; 32.792,-107.875 32.792,-25.375 ; 48.738,-107.875 48.738,-25.375 ; 77.679,-107.875 77.679,-25.375 ; 106.62,-107.875 106.62,-25.375 ; 136.482,-107.875 136.482,-25.375 ; 148.648,-107.875 148.648,-25.375 ; 19.5,-107.875 167.638,-107.875 167.638,-25.375 19.5,-25.375 19.5,-107.875 ; 20.948,-87.583 21.365,-87.583 21.781,-88 22.198,-87.583 22.615,-87.583 22.198,-87.167 22.615,-86.75 22.198,-86.75 21.781,-86.333 21.365,-86.75 20.948,-86.75 21.365,-87.167 20.948,-87.583 ; 20.948,-54.25 22.615,-54.25 22.615,-52.583 20.948,-52.583 20.948,-54.25 ; 21.281,-87.417 21.531,-87.417 21.781,-87.667 22.031,-87.417 22.281,-87.417 22.031,-87.167 22.281,-86.917 22.031,-86.917 21.781,-86.667 21.531,-86.917 21.281,-86.917 21.531,-87.167 21.281,-87.417
  text ".Layer_Name" at 35.736,-19.262 h2.54
  text "Symbol" at 21.75,-28 h1.8
  text "Count" at 33.917,-28 h1.8
  text "Hole Size" at 49.863,-28 h1.8
  text "Hole Length" at 78.804,-28 h1.8
  text "Rout Path Length" at 107.745,-28 h1.8
  text "Plated" at 137.607,-28 h1.8
  text "Hole Type" at 149.773,-28 h1.8
  text "600" at 33.917,-31.75 h1.5
  text "0,200mm (7,87mil)" at 49.863,-31.75 h1.5
  text "-" at 78.804,-31.75 h1.5
  text "-" at 107.745,-31.75 h1.5
  text "PTH" at 137.607,-31.75 h1.5
  text "Round" at 149.773,-31.75 h1.5
  text "W" at 21.126,-31.85 h1.67
  text "1002" at 33.917,-35.5 h1.5
  text "0,250mm (9,84mil)" at 49.863,-35.5 h1.5
  text "-" at 78.804,-35.5 h1.5
  text "-" at 107.745,-35.5 h1.5
  text "PTH" at 137.607,-35.5 h1.5
  text "Round" at 149.773,-35.5 h1.5
  text "X" at 21.126,-35.6 h1.67
  text "120" at 33.917,-39.25 h1.5
  text "0,500mm (19,69mil)" at 49.863,-39.25 h1.5
  text "-" at 78.804,-39.25 h1.5
  text "-" at 107.745,-39.25 h1.5
  text "PTH" at 137.607,-39.25 h1.5
  text "Round" at 149.773,-39.25 h1.5
  text "H" at 21.126,-39.35 h1.67
  text "2" at 33.917,-43 h1.5
  text "0,813mm (32,00mil)" at 49.863,-43 h1.5
  text "-" at 78.804,-43 h1.5
  text "-" at 107.745,-43 h1.5
  text "NPTH" at 137.607,-43 h1.5
  text "Round" at 149.773,-43 h1.5
  text "S" at 21.126,-43.1 h1.67
  text "10" at 33.917,-46.75 h1.5
  text "0,889mm (35,00mil)" at 49.863,-46.75 h1.5
  text "-" at 78.804,-46.75 h1.5
  text "-" at 107.745,-46.75 h1.5
  text "PTH" at 137.607,-46.75 h1.5
  text "Round" at 149.773,-46.75 h1.5
  text "K" at 21.126,-46.85 h1.67
  text "14" at 33.917,-50.5 h1.5
  text "0,900mm (35,43mil)" at 49.863,-50.5 h1.5
  text "-" at 78.804,-50.5 h1.5
  text "-" at 107.745,-50.5 h1.5
  text "PTH" at 137.607,-50.5 h1.5
  text "Round" at 149.773,-50.5 h1.5
  text "J" at 21.126,-50.6 h1.67
  text "9" at 33.917,-54.25 h1.5
  text "0,991mm (39,00mil)" at 49.863,-54.25 h1.5
  text "-" at 78.804,-54.25 h1.5
  text "-" at 107.745,-54.25 h1.5
  text "NPTH" at 137.607,-54.25 h1.5
  text "Round" at 149.773,-54.25 h1.5
  text "8" at 33.917,-58 h1.5
  text "1,016mm (40,00mil)" at 49.863,-58 h1.5
  text "-" at 78.804,-58 h1.5
  text "-" at 107.745,-58 h1.5
  text "PTH" at 137.607,-58 h1.5
  text "Round" at 149.773,-58 h1.5
  text "I" at 21.404,-58.1 h1.67
  text "2" at 33.917,-61.75 h1.5
  text "1,020mm (40,16mil)" at 49.863,-61.75 h1.5
  text "-" at 78.804,-61.75 h1.5
  text "-" at 107.745,-61.75 h1.5
  text "PTH" at 137.607,-61.75 h1.5
  text "Round" at 149.773,-61.75 h1.5
  text "U" at 21.126,-61.85 h1.67
  text "1" at 33.917,-65.5 h1.5
  text "1,100mm (43,31mil)" at 49.863,-65.5 h1.5
  text "-" at 78.804,-65.5 h1.5
  text "-" at 107.745,-65.5 h1.5
  text "NPTH" at 137.607,-65.5 h1.5
  text "Round" at 149.773,-65.5 h1.5
  text "R" at 21.126,-65.6 h1.67
  text "2" at 33.917,-69.25 h1.5
  text "1,143mm (45,00mil)" at 49.863,-69.25 h1.5
  text "-" at 78.804,-69.25 h1.5
  text "-" at 107.745,-69.25 h1.5
  text "PTH" at 137.607,-69.25 h1.5
  text "Round" at 149.773,-69.25 h1.5
  text "V" at 21.126,-69.35 h1.67
  text "3" at 33.917,-73 h1.5
  text "1,600mm (62,99mil)" at 49.863,-73 h1.5
  text "-" at 78.804,-73 h1.5
  text "-" at 107.745,-73 h1.5
  text "NPTH" at 137.607,-73 h1.5
  text "Round" at 149.773,-73 h1.5
  text "Q" at 21.126,-73.1 h1.67
  text "4" at 33.917,-76.75 h1.5
  text "1,600mm (63,00mil)" at 49.863,-76.75 h1.5
  text "-" at 78.804,-76.75 h1.5
  text "-" at 107.745,-76.75 h1.5
  text "PTH" at 137.607,-76.75 h1.5
  text "Round" at 149.773,-76.75 h1.5
  text "M" at 21.126,-76.85 h1.67
  text "1" at 33.917,-80.5 h1.5
  text "2,362mm (93,00mil)" at 49.863,-80.5 h1.5
  text "-" at 78.804,-80.5 h1.5
  text "-" at 107.745,-80.5 h1.5
  text "NPTH" at 137.607,-80.5 h1.5
  text "Round" at 149.773,-80.5 h1.5
  text "O" at 21.126,-80.6 h1.67
  text "4" at 33.917,-84.25 h1.5
  text "2,362mm (93,00mil)" at 49.863,-84.25 h1.5
  text "-" at 78.804,-84.25 h1.5
  text "-" at 107.745,-84.25 h1.5
  text "PTH" at 137.607,-84.25 h1.5
  text "Round" at 149.773,-84.25 h1.5
  text "T" at 21.126,-84.35 h1.67
  text "3" at 33.917,-88 h1.5
  text "2,600mm (102,36mil)" at 49.863,-88 h1.5
  text "-" at 78.804,-88 h1.5
  text "-" at 107.745,-88 h1.5
  text "PTH" at 137.607,-88 h1.5
  text "Round" at 149.773,-88 h1.5
  text "4" at 33.917,-91.75 h1.5
  text "3,175mm (125,00mil)" at 49.863,-91.75 h1.5
  text "-" at 78.804,-91.75 h1.5
  text "-" at 107.745,-91.75 h1.5
  text "NPTH" at 137.607,-91.75 h1.5
  text "Round" at 149.773,-91.75 h1.5
  text "N" at 21.126,-91.85 h1.67
  text "4" at 33.917,-95.5 h1.5
  text "3,200mm (125,98mil)" at 49.863,-95.5 h1.5
  text "-" at 78.804,-95.5 h1.5
  text "-" at 107.745,-95.5 h1.5
  text "PTH" at 137.607,-95.5 h1.5
  text "Round" at 149.773,-95.5 h1.5
  text "D" at 21.126,-95.6 h1.67
  text "4" at 33.917,-99.25 h1.5
  text "3,200mm (126,00mil)" at 49.863,-99.25 h1.5
  text "-" at 78.804,-99.25 h1.5
  text "-" at 107.745,-99.25 h1.5
  text "NPTH" at 137.607,-99.25 h1.5
  text "Round" at 149.773,-99.25 h1.5
  text "L" at 21.126,-99.35 h1.67
  text "3" at 33.917,-103 h1.5
  text "1,016mm (40,00mil)" at 49.863,-103 h1.5
  text "3,200mm (126,00mil)" at 78.804,-103 h1.5
  text "2,184mm (86,00mil)" at 107.745,-103 h1.5
  text "PTH" at 137.607,-103 h1.5
  text "Slot" at 149.773,-103 h1.5
  text "P" at 21.126,-103.1 h1.67
  text "1800 Total" at 33.917,-106.75 h1.5
  text "Slot definitions :" at 21.75,-110.074 h1.5
  text "Rout Path Length" at 47.147,-110.074 h1.5
  text "= Calculated from tool start centre position to tool end centre position." at 71.295,-110.074 h1.5
  text "Hole Length" at 47.147,-112.274 h1.5
  text "= Rout Path Length + Tool Size = Slot length as defined in the PCB layout" at 64.047,-112.274 h1.5

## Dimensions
0,72 to 100,72 on Sheet Graphics
0,72 to 102.5,72 on Sheet Graphics
202.5,72 to 205,72 on Sheet Graphics
0,72 to 0,0 on Sheet Graphics
-15,79.5 to 0,72 on Sheet Graphics
-15,79.5 to 320,79.5 on Sheet Graphics
-15,79.5 to -15,-11.5 on Sheet Graphics
-15,-11.5 to 0,0 on Sheet Graphics
305,0 to 306.25,-4 on Sheet Graphics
